VERSION 5.7 ;
BUSBITCHARS "[]" ;
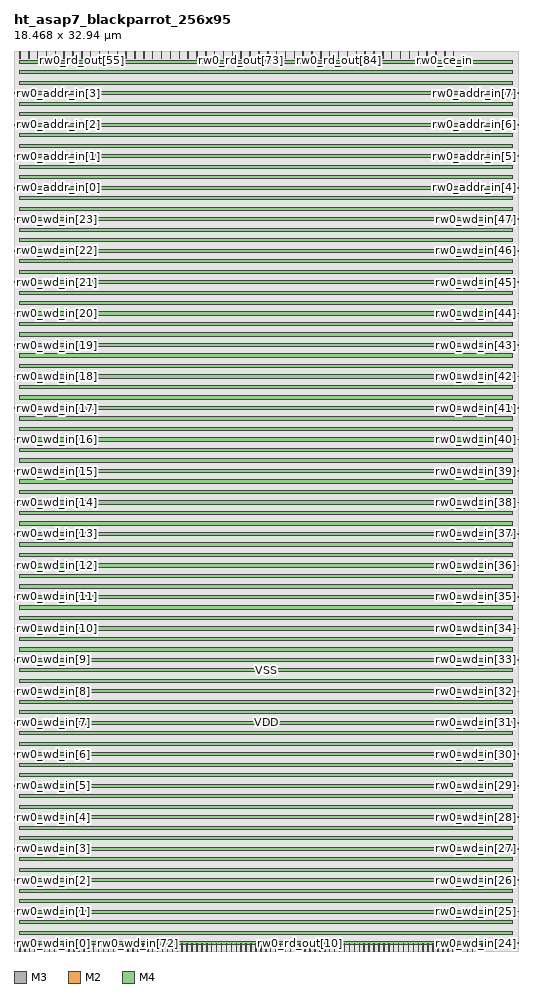
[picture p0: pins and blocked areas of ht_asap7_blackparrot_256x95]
MACRO ht_asap7_blackparrot_256x95
  FOREIGN ht_asap7_blackparrot_256x95 0 0 ;
  SYMMETRY X Y R90 ;
  SIZE 18.468 BY 32.940 ;
  CLASS BLOCK ;
  PIN rw0_wd_in[0]
    DIRECTION INPUT ;
    USE SIGNAL ;
    SHAPE ABUTMENT ;
    PORT
      LAYER M3 ;
      RECT 0.000 0.276 0.072 0.300 ;
    END
  END rw0_wd_in[0]
  PIN rw0_wd_in[1]
    DIRECTION INPUT ;
    USE SIGNAL ;
    SHAPE ABUTMENT ;
    PORT
      LAYER M3 ;
      RECT 0.000 1.428 0.072 1.452 ;
    END
  END rw0_wd_in[1]
  PIN rw0_wd_in[2]
    DIRECTION INPUT ;
    USE SIGNAL ;
    SHAPE ABUTMENT ;
    PORT
      LAYER M3 ;
      RECT 0.000 2.580 0.072 2.604 ;
    END
  END rw0_wd_in[2]
  PIN rw0_wd_in[3]
    DIRECTION INPUT ;
    USE SIGNAL ;
    SHAPE ABUTMENT ;
    PORT
      LAYER M3 ;
      RECT 0.000 3.732 0.072 3.756 ;
    END
  END rw0_wd_in[3]
  PIN rw0_wd_in[4]
    DIRECTION INPUT ;
    USE SIGNAL ;
    SHAPE ABUTMENT ;
    PORT
      LAYER M3 ;
      RECT 0.000 4.884 0.072 4.908 ;
    END
  END rw0_wd_in[4]
  PIN rw0_wd_in[5]
    DIRECTION INPUT ;
    USE SIGNAL ;
    SHAPE ABUTMENT ;
    PORT
      LAYER M3 ;
      RECT 0.000 6.036 0.072 6.060 ;
    END
  END rw0_wd_in[5]
  PIN rw0_wd_in[6]
    DIRECTION INPUT ;
    USE SIGNAL ;
    SHAPE ABUTMENT ;
    PORT
      LAYER M3 ;
      RECT 0.000 7.188 0.072 7.212 ;
    END
  END rw0_wd_in[6]
  PIN rw0_wd_in[7]
    DIRECTION INPUT ;
    USE SIGNAL ;
    SHAPE ABUTMENT ;
    PORT
      LAYER M3 ;
      RECT 0.000 8.340 0.072 8.364 ;
    END
  END rw0_wd_in[7]
  PIN rw0_wd_in[8]
    DIRECTION INPUT ;
    USE SIGNAL ;
    SHAPE ABUTMENT ;
    PORT
      LAYER M3 ;
      RECT 0.000 9.492 0.072 9.516 ;
    END
  END rw0_wd_in[8]
  PIN rw0_wd_in[9]
    DIRECTION INPUT ;
    USE SIGNAL ;
    SHAPE ABUTMENT ;
    PORT
      LAYER M3 ;
      RECT 0.000 10.644 0.072 10.668 ;
    END
  END rw0_wd_in[9]
  PIN rw0_wd_in[10]
    DIRECTION INPUT ;
    USE SIGNAL ;
    SHAPE ABUTMENT ;
    PORT
      LAYER M3 ;
      RECT 0.000 11.796 0.072 11.820 ;
    END
  END rw0_wd_in[10]
  PIN rw0_wd_in[11]
    DIRECTION INPUT ;
    USE SIGNAL ;
    SHAPE ABUTMENT ;
    PORT
      LAYER M3 ;
      RECT 0.000 12.948 0.072 12.972 ;
    END
  END rw0_wd_in[11]
  PIN rw0_wd_in[12]
    DIRECTION INPUT ;
    USE SIGNAL ;
    SHAPE ABUTMENT ;
    PORT
      LAYER M3 ;
      RECT 0.000 14.100 0.072 14.124 ;
    END
  END rw0_wd_in[12]
  PIN rw0_wd_in[13]
    DIRECTION INPUT ;
    USE SIGNAL ;
    SHAPE ABUTMENT ;
    PORT
      LAYER M3 ;
      RECT 0.000 15.252 0.072 15.276 ;
    END
  END rw0_wd_in[13]
  PIN rw0_wd_in[14]
    DIRECTION INPUT ;
    USE SIGNAL ;
    SHAPE ABUTMENT ;
    PORT
      LAYER M3 ;
      RECT 0.000 16.404 0.072 16.428 ;
    END
  END rw0_wd_in[14]
  PIN rw0_wd_in[15]
    DIRECTION INPUT ;
    USE SIGNAL ;
    SHAPE ABUTMENT ;
    PORT
      LAYER M3 ;
      RECT 0.000 17.556 0.072 17.580 ;
    END
  END rw0_wd_in[15]
  PIN rw0_wd_in[16]
    DIRECTION INPUT ;
    USE SIGNAL ;
    SHAPE ABUTMENT ;
    PORT
      LAYER M3 ;
      RECT 0.000 18.708 0.072 18.732 ;
    END
  END rw0_wd_in[16]
  PIN rw0_wd_in[17]
    DIRECTION INPUT ;
    USE SIGNAL ;
    SHAPE ABUTMENT ;
    PORT
      LAYER M3 ;
      RECT 0.000 19.860 0.072 19.884 ;
    END
  END rw0_wd_in[17]
  PIN rw0_wd_in[18]
    DIRECTION INPUT ;
    USE SIGNAL ;
    SHAPE ABUTMENT ;
    PORT
      LAYER M3 ;
      RECT 0.000 21.012 0.072 21.036 ;
    END
  END rw0_wd_in[18]
  PIN rw0_wd_in[19]
    DIRECTION INPUT ;
    USE SIGNAL ;
    SHAPE ABUTMENT ;
    PORT
      LAYER M3 ;
      RECT 0.000 22.164 0.072 22.188 ;
    END
  END rw0_wd_in[19]
  PIN rw0_wd_in[20]
    DIRECTION INPUT ;
    USE SIGNAL ;
    SHAPE ABUTMENT ;
    PORT
      LAYER M3 ;
      RECT 0.000 23.316 0.072 23.340 ;
    END
  END rw0_wd_in[20]
  PIN rw0_wd_in[21]
    DIRECTION INPUT ;
    USE SIGNAL ;
    SHAPE ABUTMENT ;
    PORT
      LAYER M3 ;
      RECT 0.000 24.468 0.072 24.492 ;
    END
  END rw0_wd_in[21]
  PIN rw0_wd_in[22]
    DIRECTION INPUT ;
    USE SIGNAL ;
    SHAPE ABUTMENT ;
    PORT
      LAYER M3 ;
      RECT 0.000 25.620 0.072 25.644 ;
    END
  END rw0_wd_in[22]
  PIN rw0_wd_in[23]
    DIRECTION INPUT ;
    USE SIGNAL ;
    SHAPE ABUTMENT ;
    PORT
      LAYER M3 ;
      RECT 0.000 26.772 0.072 26.796 ;
    END
  END rw0_wd_in[23]
  PIN rw0_wd_in[24]
    DIRECTION INPUT ;
    USE SIGNAL ;
    SHAPE ABUTMENT ;
    PORT
      LAYER M3 ;
      RECT 18.396 0.276 18.468 0.300 ;
    END
  END rw0_wd_in[24]
  PIN rw0_wd_in[25]
    DIRECTION INPUT ;
    USE SIGNAL ;
    SHAPE ABUTMENT ;
    PORT
      LAYER M3 ;
      RECT 18.396 1.428 18.468 1.452 ;
    END
  END rw0_wd_in[25]
  PIN rw0_wd_in[26]
    DIRECTION INPUT ;
    USE SIGNAL ;
    SHAPE ABUTMENT ;
    PORT
      LAYER M3 ;
      RECT 18.396 2.580 18.468 2.604 ;
    END
  END rw0_wd_in[26]
  PIN rw0_wd_in[27]
    DIRECTION INPUT ;
    USE SIGNAL ;
    SHAPE ABUTMENT ;
    PORT
      LAYER M3 ;
      RECT 18.396 3.732 18.468 3.756 ;
    END
  END rw0_wd_in[27]
  PIN rw0_wd_in[28]
    DIRECTION INPUT ;
    USE SIGNAL ;
    SHAPE ABUTMENT ;
    PORT
      LAYER M3 ;
      RECT 18.396 4.884 18.468 4.908 ;
    END
  END rw0_wd_in[28]
  PIN rw0_wd_in[29]
    DIRECTION INPUT ;
    USE SIGNAL ;
    SHAPE ABUTMENT ;
    PORT
      LAYER M3 ;
      RECT 18.396 6.036 18.468 6.060 ;
    END
  END rw0_wd_in[29]
  PIN rw0_wd_in[30]
    DIRECTION INPUT ;
    USE SIGNAL ;
    SHAPE ABUTMENT ;
    PORT
      LAYER M3 ;
      RECT 18.396 7.188 18.468 7.212 ;
    END
  END rw0_wd_in[30]
  PIN rw0_wd_in[31]
    DIRECTION INPUT ;
    USE SIGNAL ;
    SHAPE ABUTMENT ;
    PORT
      LAYER M3 ;
      RECT 18.396 8.340 18.468 8.364 ;
    END
  END rw0_wd_in[31]
  PIN rw0_wd_in[32]
    DIRECTION INPUT ;
    USE SIGNAL ;
    SHAPE ABUTMENT ;
    PORT
      LAYER M3 ;
      RECT 18.396 9.492 18.468 9.516 ;
    END
  END rw0_wd_in[32]
  PIN rw0_wd_in[33]
    DIRECTION INPUT ;
    USE SIGNAL ;
    SHAPE ABUTMENT ;
    PORT
      LAYER M3 ;
      RECT 18.396 10.644 18.468 10.668 ;
    END
  END rw0_wd_in[33]
  PIN rw0_wd_in[34]
    DIRECTION INPUT ;
    USE SIGNAL ;
    SHAPE ABUTMENT ;
    PORT
      LAYER M3 ;
      RECT 18.396 11.796 18.468 11.820 ;
    END
  END rw0_wd_in[34]
  PIN rw0_wd_in[35]
    DIRECTION INPUT ;
    USE SIGNAL ;
    SHAPE ABUTMENT ;
    PORT
      LAYER M3 ;
      RECT 18.396 12.948 18.468 12.972 ;
    END
  END rw0_wd_in[35]
  PIN rw0_wd_in[36]
    DIRECTION INPUT ;
    USE SIGNAL ;
    SHAPE ABUTMENT ;
    PORT
      LAYER M3 ;
      RECT 18.396 14.100 18.468 14.124 ;
    END
  END rw0_wd_in[36]
  PIN rw0_wd_in[37]
    DIRECTION INPUT ;
    USE SIGNAL ;
    SHAPE ABUTMENT ;
    PORT
      LAYER M3 ;
      RECT 18.396 15.252 18.468 15.276 ;
    END
  END rw0_wd_in[37]
  PIN rw0_wd_in[38]
    DIRECTION INPUT ;
    USE SIGNAL ;
    SHAPE ABUTMENT ;
    PORT
      LAYER M3 ;
      RECT 18.396 16.404 18.468 16.428 ;
    END
  END rw0_wd_in[38]
  PIN rw0_wd_in[39]
    DIRECTION INPUT ;
    USE SIGNAL ;
    SHAPE ABUTMENT ;
    PORT
      LAYER M3 ;
      RECT 18.396 17.556 18.468 17.580 ;
    END
  END rw0_wd_in[39]
  PIN rw0_wd_in[40]
    DIRECTION INPUT ;
    USE SIGNAL ;
    SHAPE ABUTMENT ;
    PORT
      LAYER M3 ;
      RECT 18.396 18.708 18.468 18.732 ;
    END
  END rw0_wd_in[40]
  PIN rw0_wd_in[41]
    DIRECTION INPUT ;
    USE SIGNAL ;
    SHAPE ABUTMENT ;
    PORT
      LAYER M3 ;
      RECT 18.396 19.860 18.468 19.884 ;
    END
  END rw0_wd_in[41]
  PIN rw0_wd_in[42]
    DIRECTION INPUT ;
    USE SIGNAL ;
    SHAPE ABUTMENT ;
    PORT
      LAYER M3 ;
      RECT 18.396 21.012 18.468 21.036 ;
    END
  END rw0_wd_in[42]
  PIN rw0_wd_in[43]
    DIRECTION INPUT ;
    USE SIGNAL ;
    SHAPE ABUTMENT ;
    PORT
      LAYER M3 ;
      RECT 18.396 22.164 18.468 22.188 ;
    END
  END rw0_wd_in[43]
  PIN rw0_wd_in[44]
    DIRECTION INPUT ;
    USE SIGNAL ;
    SHAPE ABUTMENT ;
    PORT
      LAYER M3 ;
      RECT 18.396 23.316 18.468 23.340 ;
    END
  END rw0_wd_in[44]
  PIN rw0_wd_in[45]
    DIRECTION INPUT ;
    USE SIGNAL ;
    SHAPE ABUTMENT ;
    PORT
      LAYER M3 ;
      RECT 18.396 24.468 18.468 24.492 ;
    END
  END rw0_wd_in[45]
  PIN rw0_wd_in[46]
    DIRECTION INPUT ;
    USE SIGNAL ;
    SHAPE ABUTMENT ;
    PORT
      LAYER M3 ;
      RECT 18.396 25.620 18.468 25.644 ;
    END
  END rw0_wd_in[46]
  PIN rw0_wd_in[47]
    DIRECTION INPUT ;
    USE SIGNAL ;
    SHAPE ABUTMENT ;
    PORT
      LAYER M3 ;
      RECT 18.396 26.772 18.468 26.796 ;
    END
  END rw0_wd_in[47]
  PIN rw0_wd_in[48]
    DIRECTION INPUT ;
    USE SIGNAL ;
    SHAPE ABUTMENT ;
    PORT
      LAYER M2 ;
      RECT 0.207 0.000 0.225 0.270 ;
    END
  END rw0_wd_in[48]
  PIN rw0_wd_in[49]
    DIRECTION INPUT ;
    USE SIGNAL ;
    SHAPE ABUTMENT ;
    PORT
      LAYER M2 ;
      RECT 0.387 0.000 0.405 0.270 ;
    END
  END rw0_wd_in[49]
  PIN rw0_wd_in[50]
    DIRECTION INPUT ;
    USE SIGNAL ;
    SHAPE ABUTMENT ;
    PORT
      LAYER M2 ;
      RECT 0.567 0.000 0.585 0.270 ;
    END
  END rw0_wd_in[50]
  PIN rw0_wd_in[51]
    DIRECTION INPUT ;
    USE SIGNAL ;
    SHAPE ABUTMENT ;
    PORT
      LAYER M2 ;
      RECT 0.747 0.000 0.765 0.270 ;
    END
  END rw0_wd_in[51]
  PIN rw0_wd_in[52]
    DIRECTION INPUT ;
    USE SIGNAL ;
    SHAPE ABUTMENT ;
    PORT
      LAYER M2 ;
      RECT 0.927 0.000 0.945 0.270 ;
    END
  END rw0_wd_in[52]
  PIN rw0_wd_in[53]
    DIRECTION INPUT ;
    USE SIGNAL ;
    SHAPE ABUTMENT ;
    PORT
      LAYER M2 ;
      RECT 1.107 0.000 1.125 0.270 ;
    END
  END rw0_wd_in[53]
  PIN rw0_wd_in[54]
    DIRECTION INPUT ;
    USE SIGNAL ;
    SHAPE ABUTMENT ;
    PORT
      LAYER M2 ;
      RECT 1.287 0.000 1.305 0.270 ;
    END
  END rw0_wd_in[54]
  PIN rw0_wd_in[55]
    DIRECTION INPUT ;
    USE SIGNAL ;
    SHAPE ABUTMENT ;
    PORT
      LAYER M2 ;
      RECT 1.467 0.000 1.485 0.270 ;
    END
  END rw0_wd_in[55]
  PIN rw0_wd_in[56]
    DIRECTION INPUT ;
    USE SIGNAL ;
    SHAPE ABUTMENT ;
    PORT
      LAYER M2 ;
      RECT 1.647 0.000 1.665 0.270 ;
    END
  END rw0_wd_in[56]
  PIN rw0_wd_in[57]
    DIRECTION INPUT ;
    USE SIGNAL ;
    SHAPE ABUTMENT ;
    PORT
      LAYER M2 ;
      RECT 1.827 0.000 1.845 0.270 ;
    END
  END rw0_wd_in[57]
  PIN rw0_wd_in[58]
    DIRECTION INPUT ;
    USE SIGNAL ;
    SHAPE ABUTMENT ;
    PORT
      LAYER M2 ;
      RECT 2.007 0.000 2.025 0.270 ;
    END
  END rw0_wd_in[58]
  PIN rw0_wd_in[59]
    DIRECTION INPUT ;
    USE SIGNAL ;
    SHAPE ABUTMENT ;
    PORT
      LAYER M2 ;
      RECT 2.187 0.000 2.205 0.270 ;
    END
  END rw0_wd_in[59]
  PIN rw0_wd_in[60]
    DIRECTION INPUT ;
    USE SIGNAL ;
    SHAPE ABUTMENT ;
    PORT
      LAYER M2 ;
      RECT 2.367 0.000 2.385 0.270 ;
    END
  END rw0_wd_in[60]
  PIN rw0_wd_in[61]
    DIRECTION INPUT ;
    USE SIGNAL ;
    SHAPE ABUTMENT ;
    PORT
      LAYER M2 ;
      RECT 2.547 0.000 2.565 0.270 ;
    END
  END rw0_wd_in[61]
  PIN rw0_wd_in[62]
    DIRECTION INPUT ;
    USE SIGNAL ;
    SHAPE ABUTMENT ;
    PORT
      LAYER M2 ;
      RECT 2.727 0.000 2.745 0.270 ;
    END
  END rw0_wd_in[62]
  PIN rw0_wd_in[63]
    DIRECTION INPUT ;
    USE SIGNAL ;
    SHAPE ABUTMENT ;
    PORT
      LAYER M2 ;
      RECT 2.907 0.000 2.925 0.270 ;
    END
  END rw0_wd_in[63]
  PIN rw0_wd_in[64]
    DIRECTION INPUT ;
    USE SIGNAL ;
    SHAPE ABUTMENT ;
    PORT
      LAYER M2 ;
      RECT 3.087 0.000 3.105 0.270 ;
    END
  END rw0_wd_in[64]
  PIN rw0_wd_in[65]
    DIRECTION INPUT ;
    USE SIGNAL ;
    SHAPE ABUTMENT ;
    PORT
      LAYER M2 ;
      RECT 3.267 0.000 3.285 0.270 ;
    END
  END rw0_wd_in[65]
  PIN rw0_wd_in[66]
    DIRECTION INPUT ;
    USE SIGNAL ;
    SHAPE ABUTMENT ;
    PORT
      LAYER M2 ;
      RECT 3.447 0.000 3.465 0.270 ;
    END
  END rw0_wd_in[66]
  PIN rw0_wd_in[67]
    DIRECTION INPUT ;
    USE SIGNAL ;
    SHAPE ABUTMENT ;
    PORT
      LAYER M2 ;
      RECT 3.627 0.000 3.645 0.270 ;
    END
  END rw0_wd_in[67]
  PIN rw0_wd_in[68]
    DIRECTION INPUT ;
    USE SIGNAL ;
    SHAPE ABUTMENT ;
    PORT
      LAYER M2 ;
      RECT 3.807 0.000 3.825 0.270 ;
    END
  END rw0_wd_in[68]
  PIN rw0_wd_in[69]
    DIRECTION INPUT ;
    USE SIGNAL ;
    SHAPE ABUTMENT ;
    PORT
      LAYER M2 ;
      RECT 3.987 0.000 4.005 0.270 ;
    END
  END rw0_wd_in[69]
  PIN rw0_wd_in[70]
    DIRECTION INPUT ;
    USE SIGNAL ;
    SHAPE ABUTMENT ;
    PORT
      LAYER M2 ;
      RECT 4.167 0.000 4.185 0.270 ;
    END
  END rw0_wd_in[70]
  PIN rw0_wd_in[71]
    DIRECTION INPUT ;
    USE SIGNAL ;
    SHAPE ABUTMENT ;
    PORT
      LAYER M2 ;
      RECT 4.347 0.000 4.365 0.270 ;
    END
  END rw0_wd_in[71]
  PIN rw0_wd_in[72]
    DIRECTION INPUT ;
    USE SIGNAL ;
    SHAPE ABUTMENT ;
    PORT
      LAYER M2 ;
      RECT 4.527 0.000 4.545 0.270 ;
    END
  END rw0_wd_in[72]
  PIN rw0_wd_in[73]
    DIRECTION INPUT ;
    USE SIGNAL ;
    SHAPE ABUTMENT ;
    PORT
      LAYER M2 ;
      RECT 4.707 0.000 4.725 0.270 ;
    END
  END rw0_wd_in[73]
  PIN rw0_wd_in[74]
    DIRECTION INPUT ;
    USE SIGNAL ;
    SHAPE ABUTMENT ;
    PORT
      LAYER M2 ;
      RECT 4.887 0.000 4.905 0.270 ;
    END
  END rw0_wd_in[74]
  PIN rw0_wd_in[75]
    DIRECTION INPUT ;
    USE SIGNAL ;
    SHAPE ABUTMENT ;
    PORT
      LAYER M2 ;
      RECT 5.067 0.000 5.085 0.270 ;
    END
  END rw0_wd_in[75]
  PIN rw0_wd_in[76]
    DIRECTION INPUT ;
    USE SIGNAL ;
    SHAPE ABUTMENT ;
    PORT
      LAYER M2 ;
      RECT 5.247 0.000 5.265 0.270 ;
    END
  END rw0_wd_in[76]
  PIN rw0_wd_in[77]
    DIRECTION INPUT ;
    USE SIGNAL ;
    SHAPE ABUTMENT ;
    PORT
      LAYER M2 ;
      RECT 5.427 0.000 5.445 0.270 ;
    END
  END rw0_wd_in[77]
  PIN rw0_wd_in[78]
    DIRECTION INPUT ;
    USE SIGNAL ;
    SHAPE ABUTMENT ;
    PORT
      LAYER M2 ;
      RECT 5.607 0.000 5.625 0.270 ;
    END
  END rw0_wd_in[78]
  PIN rw0_wd_in[79]
    DIRECTION INPUT ;
    USE SIGNAL ;
    SHAPE ABUTMENT ;
    PORT
      LAYER M2 ;
      RECT 5.787 0.000 5.805 0.270 ;
    END
  END rw0_wd_in[79]
  PIN rw0_wd_in[80]
    DIRECTION INPUT ;
    USE SIGNAL ;
    SHAPE ABUTMENT ;
    PORT
      LAYER M2 ;
      RECT 5.967 0.000 5.985 0.270 ;
    END
  END rw0_wd_in[80]
  PIN rw0_wd_in[81]
    DIRECTION INPUT ;
    USE SIGNAL ;
    SHAPE ABUTMENT ;
    PORT
      LAYER M2 ;
      RECT 6.147 0.000 6.165 0.270 ;
    END
  END rw0_wd_in[81]
  PIN rw0_wd_in[82]
    DIRECTION INPUT ;
    USE SIGNAL ;
    SHAPE ABUTMENT ;
    PORT
      LAYER M2 ;
      RECT 6.327 0.000 6.345 0.270 ;
    END
  END rw0_wd_in[82]
  PIN rw0_wd_in[83]
    DIRECTION INPUT ;
    USE SIGNAL ;
    SHAPE ABUTMENT ;
    PORT
      LAYER M2 ;
      RECT 6.507 0.000 6.525 0.270 ;
    END
  END rw0_wd_in[83]
  PIN rw0_wd_in[84]
    DIRECTION INPUT ;
    USE SIGNAL ;
    SHAPE ABUTMENT ;
    PORT
      LAYER M2 ;
      RECT 6.687 0.000 6.705 0.270 ;
    END
  END rw0_wd_in[84]
  PIN rw0_wd_in[85]
    DIRECTION INPUT ;
    USE SIGNAL ;
    SHAPE ABUTMENT ;
    PORT
      LAYER M2 ;
      RECT 6.867 0.000 6.885 0.270 ;
    END
  END rw0_wd_in[85]
  PIN rw0_wd_in[86]
    DIRECTION INPUT ;
    USE SIGNAL ;
    SHAPE ABUTMENT ;
    PORT
      LAYER M2 ;
      RECT 7.047 0.000 7.065 0.270 ;
    END
  END rw0_wd_in[86]
  PIN rw0_wd_in[87]
    DIRECTION INPUT ;
    USE SIGNAL ;
    SHAPE ABUTMENT ;
    PORT
      LAYER M2 ;
      RECT 7.227 0.000 7.245 0.270 ;
    END
  END rw0_wd_in[87]
  PIN rw0_wd_in[88]
    DIRECTION INPUT ;
    USE SIGNAL ;
    SHAPE ABUTMENT ;
    PORT
      LAYER M2 ;
      RECT 7.407 0.000 7.425 0.270 ;
    END
  END rw0_wd_in[88]
  PIN rw0_wd_in[89]
    DIRECTION INPUT ;
    USE SIGNAL ;
    SHAPE ABUTMENT ;
    PORT
      LAYER M2 ;
      RECT 7.587 0.000 7.605 0.270 ;
    END
  END rw0_wd_in[89]
  PIN rw0_wd_in[90]
    DIRECTION INPUT ;
    USE SIGNAL ;
    SHAPE ABUTMENT ;
    PORT
      LAYER M2 ;
      RECT 7.767 0.000 7.785 0.270 ;
    END
  END rw0_wd_in[90]
  PIN rw0_wd_in[91]
    DIRECTION INPUT ;
    USE SIGNAL ;
    SHAPE ABUTMENT ;
    PORT
      LAYER M2 ;
      RECT 7.947 0.000 7.965 0.270 ;
    END
  END rw0_wd_in[91]
  PIN rw0_wd_in[92]
    DIRECTION INPUT ;
    USE SIGNAL ;
    SHAPE ABUTMENT ;
    PORT
      LAYER M2 ;
      RECT 8.127 0.000 8.145 0.270 ;
    END
  END rw0_wd_in[92]
  PIN rw0_wd_in[93]
    DIRECTION INPUT ;
    USE SIGNAL ;
    SHAPE ABUTMENT ;
    PORT
      LAYER M2 ;
      RECT 8.307 0.000 8.325 0.270 ;
    END
  END rw0_wd_in[93]
  PIN rw0_wd_in[94]
    DIRECTION INPUT ;
    USE SIGNAL ;
    SHAPE ABUTMENT ;
    PORT
      LAYER M2 ;
      RECT 8.487 0.000 8.505 0.270 ;
    END
  END rw0_wd_in[94]
  PIN rw0_rd_out[0]
    DIRECTION OUTPUT ;
    USE SIGNAL ;
    SHAPE ABUTMENT ;
    PORT
      LAYER M2 ;
      RECT 8.667 0.000 8.685 0.270 ;
    END
  END rw0_rd_out[0]
  PIN rw0_rd_out[1]
    DIRECTION OUTPUT ;
    USE SIGNAL ;
    SHAPE ABUTMENT ;
    PORT
      LAYER M2 ;
      RECT 8.847 0.000 8.865 0.270 ;
    END
  END rw0_rd_out[1]
  PIN rw0_rd_out[2]
    DIRECTION OUTPUT ;
    USE SIGNAL ;
    SHAPE ABUTMENT ;
    PORT
      LAYER M2 ;
      RECT 9.027 0.000 9.045 0.270 ;
    END
  END rw0_rd_out[2]
  PIN rw0_rd_out[3]
    DIRECTION OUTPUT ;
    USE SIGNAL ;
    SHAPE ABUTMENT ;
    PORT
      LAYER M2 ;
      RECT 9.207 0.000 9.225 0.270 ;
    END
  END rw0_rd_out[3]
  PIN rw0_rd_out[4]
    DIRECTION OUTPUT ;
    USE SIGNAL ;
    SHAPE ABUTMENT ;
    PORT
      LAYER M2 ;
      RECT 9.387 0.000 9.405 0.270 ;
    END
  END rw0_rd_out[4]
  PIN rw0_rd_out[5]
    DIRECTION OUTPUT ;
    USE SIGNAL ;
    SHAPE ABUTMENT ;
    PORT
      LAYER M2 ;
      RECT 9.567 0.000 9.585 0.270 ;
    END
  END rw0_rd_out[5]
  PIN rw0_rd_out[6]
    DIRECTION OUTPUT ;
    USE SIGNAL ;
    SHAPE ABUTMENT ;
    PORT
      LAYER M2 ;
      RECT 9.747 0.000 9.765 0.270 ;
    END
  END rw0_rd_out[6]
  PIN rw0_rd_out[7]
    DIRECTION OUTPUT ;
    USE SIGNAL ;
    SHAPE ABUTMENT ;
    PORT
      LAYER M2 ;
      RECT 9.927 0.000 9.945 0.270 ;
    END
  END rw0_rd_out[7]
  PIN rw0_rd_out[8]
    DIRECTION OUTPUT ;
    USE SIGNAL ;
    SHAPE ABUTMENT ;
    PORT
      LAYER M2 ;
      RECT 10.107 0.000 10.125 0.270 ;
    END
  END rw0_rd_out[8]
  PIN rw0_rd_out[9]
    DIRECTION OUTPUT ;
    USE SIGNAL ;
    SHAPE ABUTMENT ;
    PORT
      LAYER M2 ;
      RECT 10.287 0.000 10.305 0.270 ;
    END
  END rw0_rd_out[9]
  PIN rw0_rd_out[10]
    DIRECTION OUTPUT ;
    USE SIGNAL ;
    SHAPE ABUTMENT ;
    PORT
      LAYER M2 ;
      RECT 10.467 0.000 10.485 0.270 ;
    END
  END rw0_rd_out[10]
  PIN rw0_rd_out[11]
    DIRECTION OUTPUT ;
    USE SIGNAL ;
    SHAPE ABUTMENT ;
    PORT
      LAYER M2 ;
      RECT 10.647 0.000 10.665 0.270 ;
    END
  END rw0_rd_out[11]
  PIN rw0_rd_out[12]
    DIRECTION OUTPUT ;
    USE SIGNAL ;
    SHAPE ABUTMENT ;
    PORT
      LAYER M2 ;
      RECT 10.827 0.000 10.845 0.270 ;
    END
  END rw0_rd_out[12]
  PIN rw0_rd_out[13]
    DIRECTION OUTPUT ;
    USE SIGNAL ;
    SHAPE ABUTMENT ;
    PORT
      LAYER M2 ;
      RECT 11.007 0.000 11.025 0.270 ;
    END
  END rw0_rd_out[13]
  PIN rw0_rd_out[14]
    DIRECTION OUTPUT ;
    USE SIGNAL ;
    SHAPE ABUTMENT ;
    PORT
      LAYER M2 ;
      RECT 11.187 0.000 11.205 0.270 ;
    END
  END rw0_rd_out[14]
  PIN rw0_rd_out[15]
    DIRECTION OUTPUT ;
    USE SIGNAL ;
    SHAPE ABUTMENT ;
    PORT
      LAYER M2 ;
      RECT 11.367 0.000 11.385 0.270 ;
    END
  END rw0_rd_out[15]
  PIN rw0_rd_out[16]
    DIRECTION OUTPUT ;
    USE SIGNAL ;
    SHAPE ABUTMENT ;
    PORT
      LAYER M2 ;
      RECT 11.547 0.000 11.565 0.270 ;
    END
  END rw0_rd_out[16]
  PIN rw0_rd_out[17]
    DIRECTION OUTPUT ;
    USE SIGNAL ;
    SHAPE ABUTMENT ;
    PORT
      LAYER M2 ;
      RECT 11.727 0.000 11.745 0.270 ;
    END
  END rw0_rd_out[17]
  PIN rw0_rd_out[18]
    DIRECTION OUTPUT ;
    USE SIGNAL ;
    SHAPE ABUTMENT ;
    PORT
      LAYER M2 ;
      RECT 11.907 0.000 11.925 0.270 ;
    END
  END rw0_rd_out[18]
  PIN rw0_rd_out[19]
    DIRECTION OUTPUT ;
    USE SIGNAL ;
    SHAPE ABUTMENT ;
    PORT
      LAYER M2 ;
      RECT 12.087 0.000 12.105 0.270 ;
    END
  END rw0_rd_out[19]
  PIN rw0_rd_out[20]
    DIRECTION OUTPUT ;
    USE SIGNAL ;
    SHAPE ABUTMENT ;
    PORT
      LAYER M2 ;
      RECT 12.267 0.000 12.285 0.270 ;
    END
  END rw0_rd_out[20]
  PIN rw0_rd_out[21]
    DIRECTION OUTPUT ;
    USE SIGNAL ;
    SHAPE ABUTMENT ;
    PORT
      LAYER M2 ;
      RECT 12.447 0.000 12.465 0.270 ;
    END
  END rw0_rd_out[21]
  PIN rw0_rd_out[22]
    DIRECTION OUTPUT ;
    USE SIGNAL ;
    SHAPE ABUTMENT ;
    PORT
      LAYER M2 ;
      RECT 12.627 0.000 12.645 0.270 ;
    END
  END rw0_rd_out[22]
  PIN rw0_rd_out[23]
    DIRECTION OUTPUT ;
    USE SIGNAL ;
    SHAPE ABUTMENT ;
    PORT
      LAYER M2 ;
      RECT 12.807 0.000 12.825 0.270 ;
    END
  END rw0_rd_out[23]
  PIN rw0_rd_out[24]
    DIRECTION OUTPUT ;
    USE SIGNAL ;
    SHAPE ABUTMENT ;
    PORT
      LAYER M2 ;
      RECT 12.987 0.000 13.005 0.270 ;
    END
  END rw0_rd_out[24]
  PIN rw0_rd_out[25]
    DIRECTION OUTPUT ;
    USE SIGNAL ;
    SHAPE ABUTMENT ;
    PORT
      LAYER M2 ;
      RECT 13.167 0.000 13.185 0.270 ;
    END
  END rw0_rd_out[25]
  PIN rw0_rd_out[26]
    DIRECTION OUTPUT ;
    USE SIGNAL ;
    SHAPE ABUTMENT ;
    PORT
      LAYER M2 ;
      RECT 13.347 0.000 13.365 0.270 ;
    END
  END rw0_rd_out[26]
  PIN rw0_rd_out[27]
    DIRECTION OUTPUT ;
    USE SIGNAL ;
    SHAPE ABUTMENT ;
    PORT
      LAYER M2 ;
      RECT 13.527 0.000 13.545 0.270 ;
    END
  END rw0_rd_out[27]
  PIN rw0_rd_out[28]
    DIRECTION OUTPUT ;
    USE SIGNAL ;
    SHAPE ABUTMENT ;
    PORT
      LAYER M2 ;
      RECT 13.707 0.000 13.725 0.270 ;
    END
  END rw0_rd_out[28]
  PIN rw0_rd_out[29]
    DIRECTION OUTPUT ;
    USE SIGNAL ;
    SHAPE ABUTMENT ;
    PORT
      LAYER M2 ;
      RECT 13.887 0.000 13.905 0.270 ;
    END
  END rw0_rd_out[29]
  PIN rw0_rd_out[30]
    DIRECTION OUTPUT ;
    USE SIGNAL ;
    SHAPE ABUTMENT ;
    PORT
      LAYER M2 ;
      RECT 14.067 0.000 14.085 0.270 ;
    END
  END rw0_rd_out[30]
  PIN rw0_rd_out[31]
    DIRECTION OUTPUT ;
    USE SIGNAL ;
    SHAPE ABUTMENT ;
    PORT
      LAYER M2 ;
      RECT 14.247 0.000 14.265 0.270 ;
    END
  END rw0_rd_out[31]
  PIN rw0_rd_out[32]
    DIRECTION OUTPUT ;
    USE SIGNAL ;
    SHAPE ABUTMENT ;
    PORT
      LAYER M2 ;
      RECT 14.427 0.000 14.445 0.270 ;
    END
  END rw0_rd_out[32]
  PIN rw0_rd_out[33]
    DIRECTION OUTPUT ;
    USE SIGNAL ;
    SHAPE ABUTMENT ;
    PORT
      LAYER M2 ;
      RECT 14.607 0.000 14.625 0.270 ;
    END
  END rw0_rd_out[33]
  PIN rw0_rd_out[34]
    DIRECTION OUTPUT ;
    USE SIGNAL ;
    SHAPE ABUTMENT ;
    PORT
      LAYER M2 ;
      RECT 14.787 0.000 14.805 0.270 ;
    END
  END rw0_rd_out[34]
  PIN rw0_rd_out[35]
    DIRECTION OUTPUT ;
    USE SIGNAL ;
    SHAPE ABUTMENT ;
    PORT
      LAYER M2 ;
      RECT 14.967 0.000 14.985 0.270 ;
    END
  END rw0_rd_out[35]
  PIN rw0_rd_out[36]
    DIRECTION OUTPUT ;
    USE SIGNAL ;
    SHAPE ABUTMENT ;
    PORT
      LAYER M2 ;
      RECT 15.147 0.000 15.165 0.270 ;
    END
  END rw0_rd_out[36]
  PIN rw0_rd_out[37]
    DIRECTION OUTPUT ;
    USE SIGNAL ;
    SHAPE ABUTMENT ;
    PORT
      LAYER M2 ;
      RECT 15.327 0.000 15.345 0.270 ;
    END
  END rw0_rd_out[37]
  PIN rw0_rd_out[38]
    DIRECTION OUTPUT ;
    USE SIGNAL ;
    SHAPE ABUTMENT ;
    PORT
      LAYER M2 ;
      RECT 15.507 0.000 15.525 0.270 ;
    END
  END rw0_rd_out[38]
  PIN rw0_rd_out[39]
    DIRECTION OUTPUT ;
    USE SIGNAL ;
    SHAPE ABUTMENT ;
    PORT
      LAYER M2 ;
      RECT 15.687 0.000 15.705 0.270 ;
    END
  END rw0_rd_out[39]
  PIN rw0_rd_out[40]
    DIRECTION OUTPUT ;
    USE SIGNAL ;
    SHAPE ABUTMENT ;
    PORT
      LAYER M2 ;
      RECT 15.867 0.000 15.885 0.270 ;
    END
  END rw0_rd_out[40]
  PIN rw0_rd_out[41]
    DIRECTION OUTPUT ;
    USE SIGNAL ;
    SHAPE ABUTMENT ;
    PORT
      LAYER M2 ;
      RECT 16.047 0.000 16.065 0.270 ;
    END
  END rw0_rd_out[41]
  PIN rw0_rd_out[42]
    DIRECTION OUTPUT ;
    USE SIGNAL ;
    SHAPE ABUTMENT ;
    PORT
      LAYER M2 ;
      RECT 16.227 0.000 16.245 0.270 ;
    END
  END rw0_rd_out[42]
  PIN rw0_rd_out[43]
    DIRECTION OUTPUT ;
    USE SIGNAL ;
    SHAPE ABUTMENT ;
    PORT
      LAYER M2 ;
      RECT 16.407 0.000 16.425 0.270 ;
    END
  END rw0_rd_out[43]
  PIN rw0_rd_out[44]
    DIRECTION OUTPUT ;
    USE SIGNAL ;
    SHAPE ABUTMENT ;
    PORT
      LAYER M2 ;
      RECT 16.587 0.000 16.605 0.270 ;
    END
  END rw0_rd_out[44]
  PIN rw0_rd_out[45]
    DIRECTION OUTPUT ;
    USE SIGNAL ;
    SHAPE ABUTMENT ;
    PORT
      LAYER M2 ;
      RECT 16.767 0.000 16.785 0.270 ;
    END
  END rw0_rd_out[45]
  PIN rw0_rd_out[46]
    DIRECTION OUTPUT ;
    USE SIGNAL ;
    SHAPE ABUTMENT ;
    PORT
      LAYER M2 ;
      RECT 16.947 0.000 16.965 0.270 ;
    END
  END rw0_rd_out[46]
  PIN rw0_rd_out[47]
    DIRECTION OUTPUT ;
    USE SIGNAL ;
    SHAPE ABUTMENT ;
    PORT
      LAYER M2 ;
      RECT 17.127 0.000 17.145 0.270 ;
    END
  END rw0_rd_out[47]
  PIN rw0_rd_out[48]
    DIRECTION OUTPUT ;
    USE SIGNAL ;
    SHAPE ABUTMENT ;
    PORT
      LAYER M2 ;
      RECT 0.207 32.670 0.225 32.940 ;
    END
  END rw0_rd_out[48]
  PIN rw0_rd_out[49]
    DIRECTION OUTPUT ;
    USE SIGNAL ;
    SHAPE ABUTMENT ;
    PORT
      LAYER M2 ;
      RECT 0.531 32.670 0.549 32.940 ;
    END
  END rw0_rd_out[49]
  PIN rw0_rd_out[50]
    DIRECTION OUTPUT ;
    USE SIGNAL ;
    SHAPE ABUTMENT ;
    PORT
      LAYER M2 ;
      RECT 0.855 32.670 0.873 32.940 ;
    END
  END rw0_rd_out[50]
  PIN rw0_rd_out[51]
    DIRECTION OUTPUT ;
    USE SIGNAL ;
    SHAPE ABUTMENT ;
    PORT
      LAYER M2 ;
      RECT 1.179 32.670 1.197 32.940 ;
    END
  END rw0_rd_out[51]
  PIN rw0_rd_out[52]
    DIRECTION OUTPUT ;
    USE SIGNAL ;
    SHAPE ABUTMENT ;
    PORT
      LAYER M2 ;
      RECT 1.503 32.670 1.521 32.940 ;
    END
  END rw0_rd_out[52]
  PIN rw0_rd_out[53]
    DIRECTION OUTPUT ;
    USE SIGNAL ;
    SHAPE ABUTMENT ;
    PORT
      LAYER M2 ;
      RECT 1.827 32.670 1.845 32.940 ;
    END
  END rw0_rd_out[53]
  PIN rw0_rd_out[54]
    DIRECTION OUTPUT ;
    USE SIGNAL ;
    SHAPE ABUTMENT ;
    PORT
      LAYER M2 ;
      RECT 2.151 32.670 2.169 32.940 ;
    END
  END rw0_rd_out[54]
  PIN rw0_rd_out[55]
    DIRECTION OUTPUT ;
    USE SIGNAL ;
    SHAPE ABUTMENT ;
    PORT
      LAYER M2 ;
      RECT 2.475 32.670 2.493 32.940 ;
    END
  END rw0_rd_out[55]
  PIN rw0_rd_out[56]
    DIRECTION OUTPUT ;
    USE SIGNAL ;
    SHAPE ABUTMENT ;
    PORT
      LAYER M2 ;
      RECT 2.799 32.670 2.817 32.940 ;
    END
  END rw0_rd_out[56]
  PIN rw0_rd_out[57]
    DIRECTION OUTPUT ;
    USE SIGNAL ;
    SHAPE ABUTMENT ;
    PORT
      LAYER M2 ;
      RECT 3.123 32.670 3.141 32.940 ;
    END
  END rw0_rd_out[57]
  PIN rw0_rd_out[58]
    DIRECTION OUTPUT ;
    USE SIGNAL ;
    SHAPE ABUTMENT ;
    PORT
      LAYER M2 ;
      RECT 3.447 32.670 3.465 32.940 ;
    END
  END rw0_rd_out[58]
  PIN rw0_rd_out[59]
    DIRECTION OUTPUT ;
    USE SIGNAL ;
    SHAPE ABUTMENT ;
    PORT
      LAYER M2 ;
      RECT 3.771 32.670 3.789 32.940 ;
    END
  END rw0_rd_out[59]
  PIN rw0_rd_out[60]
    DIRECTION OUTPUT ;
    USE SIGNAL ;
    SHAPE ABUTMENT ;
    PORT
      LAYER M2 ;
      RECT 4.095 32.670 4.113 32.940 ;
    END
  END rw0_rd_out[60]
  PIN rw0_rd_out[61]
    DIRECTION OUTPUT ;
    USE SIGNAL ;
    SHAPE ABUTMENT ;
    PORT
      LAYER M2 ;
      RECT 4.419 32.670 4.437 32.940 ;
    END
  END rw0_rd_out[61]
  PIN rw0_rd_out[62]
    DIRECTION OUTPUT ;
    USE SIGNAL ;
    SHAPE ABUTMENT ;
    PORT
      LAYER M2 ;
      RECT 4.743 32.670 4.761 32.940 ;
    END
  END rw0_rd_out[62]
  PIN rw0_rd_out[63]
    DIRECTION OUTPUT ;
    USE SIGNAL ;
    SHAPE ABUTMENT ;
    PORT
      LAYER M2 ;
      RECT 5.067 32.670 5.085 32.940 ;
    END
  END rw0_rd_out[63]
  PIN rw0_rd_out[64]
    DIRECTION OUTPUT ;
    USE SIGNAL ;
    SHAPE ABUTMENT ;
    PORT
      LAYER M2 ;
      RECT 5.391 32.670 5.409 32.940 ;
    END
  END rw0_rd_out[64]
  PIN rw0_rd_out[65]
    DIRECTION OUTPUT ;
    USE SIGNAL ;
    SHAPE ABUTMENT ;
    PORT
      LAYER M2 ;
      RECT 5.715 32.670 5.733 32.940 ;
    END
  END rw0_rd_out[65]
  PIN rw0_rd_out[66]
    DIRECTION OUTPUT ;
    USE SIGNAL ;
    SHAPE ABUTMENT ;
    PORT
      LAYER M2 ;
      RECT 6.039 32.670 6.057 32.940 ;
    END
  END rw0_rd_out[66]
  PIN rw0_rd_out[67]
    DIRECTION OUTPUT ;
    USE SIGNAL ;
    SHAPE ABUTMENT ;
    PORT
      LAYER M2 ;
      RECT 6.363 32.670 6.381 32.940 ;
    END
  END rw0_rd_out[67]
  PIN rw0_rd_out[68]
    DIRECTION OUTPUT ;
    USE SIGNAL ;
    SHAPE ABUTMENT ;
    PORT
      LAYER M2 ;
      RECT 6.687 32.670 6.705 32.940 ;
    END
  END rw0_rd_out[68]
  PIN rw0_rd_out[69]
    DIRECTION OUTPUT ;
    USE SIGNAL ;
    SHAPE ABUTMENT ;
    PORT
      LAYER M2 ;
      RECT 7.011 32.670 7.029 32.940 ;
    END
  END rw0_rd_out[69]
  PIN rw0_rd_out[70]
    DIRECTION OUTPUT ;
    USE SIGNAL ;
    SHAPE ABUTMENT ;
    PORT
      LAYER M2 ;
      RECT 7.335 32.670 7.353 32.940 ;
    END
  END rw0_rd_out[70]
  PIN rw0_rd_out[71]
    DIRECTION OUTPUT ;
    USE SIGNAL ;
    SHAPE ABUTMENT ;
    PORT
      LAYER M2 ;
      RECT 7.659 32.670 7.677 32.940 ;
    END
  END rw0_rd_out[71]
  PIN rw0_rd_out[72]
    DIRECTION OUTPUT ;
    USE SIGNAL ;
    SHAPE ABUTMENT ;
    PORT
      LAYER M2 ;
      RECT 7.983 32.670 8.001 32.940 ;
    END
  END rw0_rd_out[72]
  PIN rw0_rd_out[73]
    DIRECTION OUTPUT ;
    USE SIGNAL ;
    SHAPE ABUTMENT ;
    PORT
      LAYER M2 ;
      RECT 8.307 32.670 8.325 32.940 ;
    END
  END rw0_rd_out[73]
  PIN rw0_rd_out[74]
    DIRECTION OUTPUT ;
    USE SIGNAL ;
    SHAPE ABUTMENT ;
    PORT
      LAYER M2 ;
      RECT 8.631 32.670 8.649 32.940 ;
    END
  END rw0_rd_out[74]
  PIN rw0_rd_out[75]
    DIRECTION OUTPUT ;
    USE SIGNAL ;
    SHAPE ABUTMENT ;
    PORT
      LAYER M2 ;
      RECT 8.955 32.670 8.973 32.940 ;
    END
  END rw0_rd_out[75]
  PIN rw0_rd_out[76]
    DIRECTION OUTPUT ;
    USE SIGNAL ;
    SHAPE ABUTMENT ;
    PORT
      LAYER M2 ;
      RECT 9.279 32.670 9.297 32.940 ;
    END
  END rw0_rd_out[76]
  PIN rw0_rd_out[77]
    DIRECTION OUTPUT ;
    USE SIGNAL ;
    SHAPE ABUTMENT ;
    PORT
      LAYER M2 ;
      RECT 9.603 32.670 9.621 32.940 ;
    END
  END rw0_rd_out[77]
  PIN rw0_rd_out[78]
    DIRECTION OUTPUT ;
    USE SIGNAL ;
    SHAPE ABUTMENT ;
    PORT
      LAYER M2 ;
      RECT 9.927 32.670 9.945 32.940 ;
    END
  END rw0_rd_out[78]
  PIN rw0_rd_out[79]
    DIRECTION OUTPUT ;
    USE SIGNAL ;
    SHAPE ABUTMENT ;
    PORT
      LAYER M2 ;
      RECT 10.251 32.670 10.269 32.940 ;
    END
  END rw0_rd_out[79]
  PIN rw0_rd_out[80]
    DIRECTION OUTPUT ;
    USE SIGNAL ;
    SHAPE ABUTMENT ;
    PORT
      LAYER M2 ;
      RECT 10.575 32.670 10.593 32.940 ;
    END
  END rw0_rd_out[80]
  PIN rw0_rd_out[81]
    DIRECTION OUTPUT ;
    USE SIGNAL ;
    SHAPE ABUTMENT ;
    PORT
      LAYER M2 ;
      RECT 10.899 32.670 10.917 32.940 ;
    END
  END rw0_rd_out[81]
  PIN rw0_rd_out[82]
    DIRECTION OUTPUT ;
    USE SIGNAL ;
    SHAPE ABUTMENT ;
    PORT
      LAYER M2 ;
      RECT 11.223 32.670 11.241 32.940 ;
    END
  END rw0_rd_out[82]
  PIN rw0_rd_out[83]
    DIRECTION OUTPUT ;
    USE SIGNAL ;
    SHAPE ABUTMENT ;
    PORT
      LAYER M2 ;
      RECT 11.547 32.670 11.565 32.940 ;
    END
  END rw0_rd_out[83]
  PIN rw0_rd_out[84]
    DIRECTION OUTPUT ;
    USE SIGNAL ;
    SHAPE ABUTMENT ;
    PORT
      LAYER M2 ;
      RECT 11.871 32.670 11.889 32.940 ;
    END
  END rw0_rd_out[84]
  PIN rw0_rd_out[85]
    DIRECTION OUTPUT ;
    USE SIGNAL ;
    SHAPE ABUTMENT ;
    PORT
      LAYER M2 ;
      RECT 12.195 32.670 12.213 32.940 ;
    END
  END rw0_rd_out[85]
  PIN rw0_rd_out[86]
    DIRECTION OUTPUT ;
    USE SIGNAL ;
    SHAPE ABUTMENT ;
    PORT
      LAYER M2 ;
      RECT 12.519 32.670 12.537 32.940 ;
    END
  END rw0_rd_out[86]
  PIN rw0_rd_out[87]
    DIRECTION OUTPUT ;
    USE SIGNAL ;
    SHAPE ABUTMENT ;
    PORT
      LAYER M2 ;
      RECT 12.843 32.670 12.861 32.940 ;
    END
  END rw0_rd_out[87]
  PIN rw0_rd_out[88]
    DIRECTION OUTPUT ;
    USE SIGNAL ;
    SHAPE ABUTMENT ;
    PORT
      LAYER M2 ;
      RECT 13.167 32.670 13.185 32.940 ;
    END
  END rw0_rd_out[88]
  PIN rw0_rd_out[89]
    DIRECTION OUTPUT ;
    USE SIGNAL ;
    SHAPE ABUTMENT ;
    PORT
      LAYER M2 ;
      RECT 13.491 32.670 13.509 32.940 ;
    END
  END rw0_rd_out[89]
  PIN rw0_rd_out[90]
    DIRECTION OUTPUT ;
    USE SIGNAL ;
    SHAPE ABUTMENT ;
    PORT
      LAYER M2 ;
      RECT 13.815 32.670 13.833 32.940 ;
    END
  END rw0_rd_out[90]
  PIN rw0_rd_out[91]
    DIRECTION OUTPUT ;
    USE SIGNAL ;
    SHAPE ABUTMENT ;
    PORT
      LAYER M2 ;
      RECT 14.139 32.670 14.157 32.940 ;
    END
  END rw0_rd_out[91]
  PIN rw0_rd_out[92]
    DIRECTION OUTPUT ;
    USE SIGNAL ;
    SHAPE ABUTMENT ;
    PORT
      LAYER M2 ;
      RECT 14.463 32.670 14.481 32.940 ;
    END
  END rw0_rd_out[92]
  PIN rw0_rd_out[93]
    DIRECTION OUTPUT ;
    USE SIGNAL ;
    SHAPE ABUTMENT ;
    PORT
      LAYER M2 ;
      RECT 14.787 32.670 14.805 32.940 ;
    END
  END rw0_rd_out[93]
  PIN rw0_rd_out[94]
    DIRECTION OUTPUT ;
    USE SIGNAL ;
    SHAPE ABUTMENT ;
    PORT
      LAYER M2 ;
      RECT 15.111 32.670 15.129 32.940 ;
    END
  END rw0_rd_out[94]
  PIN rw0_addr_in[0]
    DIRECTION INPUT ;
    USE SIGNAL ;
    SHAPE ABUTMENT ;
    PORT
      LAYER M3 ;
      RECT 0.000 27.924 0.072 27.948 ;
    END
  END rw0_addr_in[0]
  PIN rw0_addr_in[1]
    DIRECTION INPUT ;
    USE SIGNAL ;
    SHAPE ABUTMENT ;
    PORT
      LAYER M3 ;
      RECT 0.000 29.076 0.072 29.100 ;
    END
  END rw0_addr_in[1]
  PIN rw0_addr_in[2]
    DIRECTION INPUT ;
    USE SIGNAL ;
    SHAPE ABUTMENT ;
    PORT
      LAYER M3 ;
      RECT 0.000 30.228 0.072 30.252 ;
    END
  END rw0_addr_in[2]
  PIN rw0_addr_in[3]
    DIRECTION INPUT ;
    USE SIGNAL ;
    SHAPE ABUTMENT ;
    PORT
      LAYER M3 ;
      RECT 0.000 31.380 0.072 31.404 ;
    END
  END rw0_addr_in[3]
  PIN rw0_addr_in[4]
    DIRECTION INPUT ;
    USE SIGNAL ;
    SHAPE ABUTMENT ;
    PORT
      LAYER M3 ;
      RECT 18.396 27.924 18.468 27.948 ;
    END
  END rw0_addr_in[4]
  PIN rw0_addr_in[5]
    DIRECTION INPUT ;
    USE SIGNAL ;
    SHAPE ABUTMENT ;
    PORT
      LAYER M3 ;
      RECT 18.396 29.076 18.468 29.100 ;
    END
  END rw0_addr_in[5]
  PIN rw0_addr_in[6]
    DIRECTION INPUT ;
    USE SIGNAL ;
    SHAPE ABUTMENT ;
    PORT
      LAYER M3 ;
      RECT 18.396 30.228 18.468 30.252 ;
    END
  END rw0_addr_in[6]
  PIN rw0_addr_in[7]
    DIRECTION INPUT ;
    USE SIGNAL ;
    SHAPE ABUTMENT ;
    PORT
      LAYER M3 ;
      RECT 18.396 31.380 18.468 31.404 ;
    END
  END rw0_addr_in[7]
  PIN rw0_we_in
    DIRECTION INPUT ;
    USE SIGNAL ;
    SHAPE ABUTMENT ;
    PORT
      LAYER M2 ;
      RECT 15.435 32.670 15.453 32.940 ;
    END
  END rw0_we_in
  PIN rw0_ce_in
    DIRECTION INPUT ;
    USE SIGNAL ;
    SHAPE ABUTMENT ;
    PORT
      LAYER M2 ;
      RECT 15.759 32.670 15.777 32.940 ;
    END
  END rw0_ce_in
  PIN rw0_clk
    DIRECTION INPUT ;
    USE SIGNAL ;
    SHAPE ABUTMENT ;
    PORT
      LAYER M2 ;
      RECT 16.083 32.670 16.101 32.940 ;
    END
  END rw0_clk
  PIN VSS
    DIRECTION INOUT ;
    USE GROUND ;
    PORT
      LAYER M4 ;
      RECT 0.216 0.228 18.252 0.348 ;
      RECT 0.216 0.996 18.252 1.116 ;
      RECT 0.216 1.764 18.252 1.884 ;
      RECT 0.216 2.532 18.252 2.652 ;
      RECT 0.216 3.300 18.252 3.420 ;
      RECT 0.216 4.068 18.252 4.188 ;
      RECT 0.216 4.836 18.252 4.956 ;
      RECT 0.216 5.604 18.252 5.724 ;
      RECT 0.216 6.372 18.252 6.492 ;
      RECT 0.216 7.140 18.252 7.260 ;
      RECT 0.216 7.908 18.252 8.028 ;
      RECT 0.216 8.676 18.252 8.796 ;
      RECT 0.216 9.444 18.252 9.564 ;
      RECT 0.216 10.212 18.252 10.332 ;
      RECT 0.216 10.980 18.252 11.100 ;
      RECT 0.216 11.748 18.252 11.868 ;
      RECT 0.216 12.516 18.252 12.636 ;
      RECT 0.216 13.284 18.252 13.404 ;
      RECT 0.216 14.052 18.252 14.172 ;
      RECT 0.216 14.820 18.252 14.940 ;
      RECT 0.216 15.588 18.252 15.708 ;
      RECT 0.216 16.356 18.252 16.476 ;
      RECT 0.216 17.124 18.252 17.244 ;
      RECT 0.216 17.892 18.252 18.012 ;
      RECT 0.216 18.660 18.252 18.780 ;
      RECT 0.216 19.428 18.252 19.548 ;
      RECT 0.216 20.196 18.252 20.316 ;
      RECT 0.216 20.964 18.252 21.084 ;
      RECT 0.216 21.732 18.252 21.852 ;
      RECT 0.216 22.500 18.252 22.620 ;
      RECT 0.216 23.268 18.252 23.388 ;
      RECT 0.216 24.036 18.252 24.156 ;
      RECT 0.216 24.804 18.252 24.924 ;
      RECT 0.216 25.572 18.252 25.692 ;
      RECT 0.216 26.340 18.252 26.460 ;
      RECT 0.216 27.108 18.252 27.228 ;
      RECT 0.216 27.876 18.252 27.996 ;
      RECT 0.216 28.644 18.252 28.764 ;
      RECT 0.216 29.412 18.252 29.532 ;
      RECT 0.216 30.180 18.252 30.300 ;
      RECT 0.216 30.948 18.252 31.068 ;
      RECT 0.216 31.716 18.252 31.836 ;
      RECT 0.216 32.484 18.252 32.604 ;
    END
  END VSS
  PIN VDD
    DIRECTION INOUT ;
    USE POWER ;
    PORT
      LAYER M4 ;
      RECT 0.216 0.612 18.252 0.732 ;
      RECT 0.216 1.380 18.252 1.500 ;
      RECT 0.216 2.148 18.252 2.268 ;
      RECT 0.216 2.916 18.252 3.036 ;
      RECT 0.216 3.684 18.252 3.804 ;
      RECT 0.216 4.452 18.252 4.572 ;
      RECT 0.216 5.220 18.252 5.340 ;
      RECT 0.216 5.988 18.252 6.108 ;
      RECT 0.216 6.756 18.252 6.876 ;
      RECT 0.216 7.524 18.252 7.644 ;
      RECT 0.216 8.292 18.252 8.412 ;
      RECT 0.216 9.060 18.252 9.180 ;
      RECT 0.216 9.828 18.252 9.948 ;
      RECT 0.216 10.596 18.252 10.716 ;
      RECT 0.216 11.364 18.252 11.484 ;
      RECT 0.216 12.132 18.252 12.252 ;
      RECT 0.216 12.900 18.252 13.020 ;
      RECT 0.216 13.668 18.252 13.788 ;
      RECT 0.216 14.436 18.252 14.556 ;
      RECT 0.216 15.204 18.252 15.324 ;
      RECT 0.216 15.972 18.252 16.092 ;
      RECT 0.216 16.740 18.252 16.860 ;
      RECT 0.216 17.508 18.252 17.628 ;
      RECT 0.216 18.276 18.252 18.396 ;
      RECT 0.216 19.044 18.252 19.164 ;
      RECT 0.216 19.812 18.252 19.932 ;
      RECT 0.216 20.580 18.252 20.700 ;
      RECT 0.216 21.348 18.252 21.468 ;
      RECT 0.216 22.116 18.252 22.236 ;
      RECT 0.216 22.884 18.252 23.004 ;
      RECT 0.216 23.652 18.252 23.772 ;
      RECT 0.216 24.420 18.252 24.540 ;
      RECT 0.216 25.188 18.252 25.308 ;
      RECT 0.216 25.956 18.252 26.076 ;
      RECT 0.216 26.724 18.252 26.844 ;
      RECT 0.216 27.492 18.252 27.612 ;
      RECT 0.216 28.260 18.252 28.380 ;
      RECT 0.216 29.028 18.252 29.148 ;
      RECT 0.216 29.796 18.252 29.916 ;
      RECT 0.216 30.564 18.252 30.684 ;
      RECT 0.216 31.332 18.252 31.452 ;
      RECT 0.216 32.100 18.252 32.220 ;
    END
  END VDD
  OBS
    LAYER M1 ;
    RECT 0 0 18.468 32.940 ;
    LAYER M2 ;
    RECT 0 0 18.468 32.940 ;
    LAYER M3 ;
    RECT 0 0 18.468 32.940 ;
    LAYER M4 ;
    RECT 0 0 18.468 32.940 ;
  END
END ht_asap7_blackparrot_256x95

END LIBRARY
